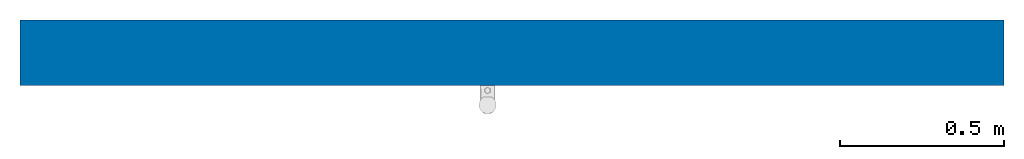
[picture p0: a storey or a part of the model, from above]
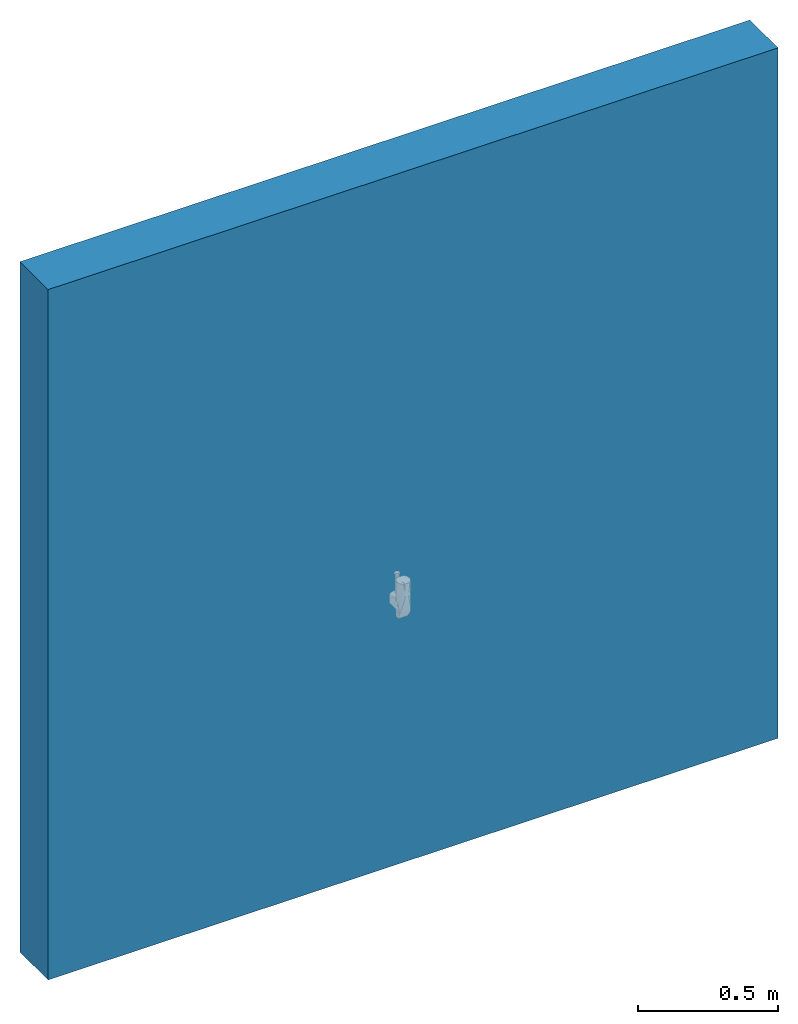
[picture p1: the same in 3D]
Properties of the parts of a building model (IFC2X3)

# File
Description: ViewDefinition [CoordinationView]
File name: Project Number
Time: 2016-07-07T09:22:54
Written by: Autodesk Revit Architecture 2011 - 1.0
Made in: 20100326_1700(x64)

# IfcProject, Project Number
Phase: Project Status

# IfcSite, Default
RefLatitude: 42, 21, 30, 344238; RefLongitude: -71, -3, -35, -194702; RefElevation: 0 mm

# IfcBuilding
Pset_BuildingCommon - NumberOfStoreys: 1
PSet_Revit_Other - Project Issue Date: Issue Date; Project Status: Project Status; Client Name: Owner; Project Address: Enter address here; Project Name: Project Name; Project Number: Project Number

# IfcBuildingStorey, Level 1
Elevation: 0 mm
PSet_Revit_Identity Data - Name: Level 1
PSet_Revit_Constraints - Elevation: 0 mm
PSet_Revit_Type_Graphics - Line Weight: 1; Color: 0; Line Pattern: Centre; Symbol: M_Level Head - Circle; Symbol at End 1 Default: no; Symbol at End 2 Default: yes
PSet_Revit_Type_Constraints - Elevation Base: 0
PSet_Revit_Type_Dimensions - Automatic Room Computation Height: no; Computation Height: 1200 mm

# IfcBuildingElementProxy: Type 1, 479406:Type 1:Type 1:129252
In: Level 1
PSet_Revit_Constraints - Level: Level 1; Elevation: 1112.49 mm
PSet_Revit_Mechanical - System Type: Domestic Cold Water; System Name: Default Domestic Cold Water (Polantis_Production)
PSet_Revit_Identity Data - Mark: 1
PSet_Revit_Phasing - Phase Created: New Construction
PSet_Revit_Type_Identity Data - URL: http://www.delabie.fr; Type Comments: Robinet électronique; Technologie: Electronique; Référence: 479406; Raccordement: M1/2"; Model: TEMPOMATIC 4; Manufacturer: DELABIE; Lien notice d'installation: http://www.delabie.fr/produits/479406; Lien fiche produit: http://www.delabie.fr/produits/479406; Lien certification: http://www.delabie.fr/produits/479406; Lien CCTP: http://www.delabie.fr/produits/479406; Hauteur: 175 mm; Finition: Métal chromé; Famille de produits: Urinoir; Débit l/s: 0,25 l/sec à 3 bar; Débit l/min: 15 l/min à 3 bar; Description: DELABIE, fabricant français, est le leader européen de l'équipement sanitaire pour les établissements recevant du public. Robinetteries, solutions pour personnes à mobilité réduite, appareils sanitaires, destinés aux écoles, lieux de loisirs, bureaux, hôpitaux, aéroports, ...; Descriptif: Robinet électronique pour urinoir individuel : Alimentation par pile 223 Lithium 6 V intégrée. Electrovanne antistagnation et module électronique intégrés dans le corps de la robinetterie. Détecteur de présence infrarouge antichoc. Prise en compte après 10 sec de présence. 3 programmes (volume de rinçage réglable selon le type d’urinoir). Mode affluence (exclusivité DELABIE) : - rinçage court après chaque utilisateur, - rinçage complémentaire à la fin de la période d’affluence. Rinçage périodique hygiénique, toutes les 24 h après la dernière utilisation : empêche le désiphonnage. Débit 0,25 l/sec à 3 bar, ajustable. Robinet d’arrêt et de réglage de débit intégré. Corps monobloc en métal chromé M1/2". Sécurité antiblocage en écoulement. Droit pour alimentation en ligne, sortie M1/2".; Alimentation électrique: Pile 6 V; OmniClass Number: 23.45.00.00; OmniClass Title: Sanitary, Laundry, and Cleaning Equipment
PSet_Revit_Type_Dimensions - Radius: 10.3 mm

# IfcWallStandardCase: Basic Wall:Generic - 200mm:398, Basic Wall:Generic - 200mm:127593
In: Level 1
Material: Default Wall 200 mm
Pset_WallCommon - Reference: Basic Wall:Generic - 200mm; LoadBearing: no; ExtendToStructure: no; IsExternal: yes
PSet_Revit_Constraints - Location Line: 0; Base Constraint: Level 1; Base Offset: 0 mm; Base is Attached: no; Base Extension Distance: 0 mm; Unconnected Height: 3000 mm; Top Offset: 0 mm; Top is Attached: no; Top Extension Distance: 0 mm; Room Bounding: yes; Related to Mass: no
PSet_Revit_Phasing - Phase Created: New Construction
PSet_Revit_Structural - Structural Usage: 0
PSet_Revit_Dimensions - Length: 3000 mm; Area: 9000000 mm2; Volume: 1800000000 mm3
PSet_Revit_Type_Construction - Wrapping at Inserts: 0; Wrapping at Ends: 0; Width: 200 mm; Function: 1
PSet_Revit_Type_Graphics - Coarse Scale Fill Color: 0
